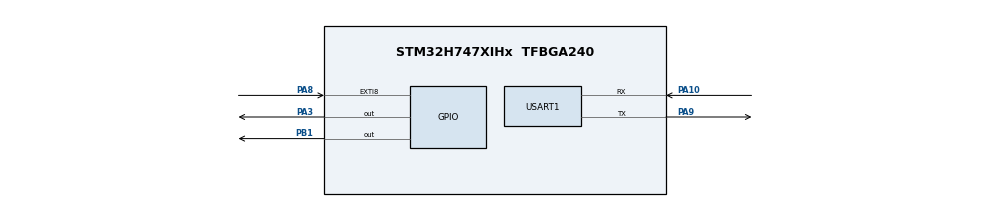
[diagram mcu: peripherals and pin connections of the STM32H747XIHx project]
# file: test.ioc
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CORTEX_M7.default_mode_Activation=1
CortexM4.IPs=CORTEX_M4\:I,FATFS_M4\:I,FREERTOS_M4\:I,IWDG2\:I,OPENAMP_M4\:I,PDM2PCM_M4\:I,PWR,RCC,RESMGR_UTILITY,SYS_M4\:I,USB_DEVICE_M4\:I,USB_HOST_M4\:I,VREFBUF,WWDG2\:I,GPIO,DMA,BDMA,MDMA,NVIC2\:I
CortexM7.IPs=CORTEX_M7\:I,FATFS_M7\:I,FREERTOS_M7\:I,IWDG1\:I,OPENAMP_M7\:I,PDM2PCM_M7\:I,PWR\:I,RCC\:I,RESMGR_UTILITY\:I,SYS\:I,USB_DEVICE_M7\:I,USB_HOST_M7\:I,VREFBUF\:I,WWDG1\:I,GPIO\:I,DMA\:I,BDMA\:I,MDMA\:I,NVIC1\:I,USART1\:I
CortexM7.Pins=PA8,PB1,PA3
Dma.Request0=USART1_TX
Dma.Request1=USART1_RX
Dma.USART1_RX.1.Direction=DMA_PERIPH_TO_MEMORY
Dma.USART1_RX.1.EventEnable=DISABLE
Dma.USART1_RX.1.FIFOMode=DMA_FIFOMODE_DISABLE
Dma.USART1_RX.1.Instance=DMA1_Stream1
Dma.USART1_RX.1.MemDataAlignment=DMA_MDATAALIGN_BYTE
Dma.USART1_RX.1.MemInc=DMA_MINC_ENABLE
Dma.USART1_RX.1.Mode=DMA_NORMAL
Dma.USART1_RX.1.PeriphDataAlignment=DMA_PDATAALIGN_BYTE
Dma.USART1_RX.1.PeriphInc=DMA_PINC_DISABLE
Dma.USART1_RX.1.Polarity=HAL_DMAMUX_REQ_GEN_RISING
Dma.USART1_RX.1.Priority=DMA_PRIORITY_LOW
Dma.USART1_RX.1.RequestNumber=1
Dma.USART1_RX.1.SignalID=NONE
Dma.USART1_RX.1.SyncEnable=DISABLE
Dma.USART1_RX.1.SyncPolarity=HAL_DMAMUX_SYNC_NO_EVENT
Dma.USART1_RX.1.SyncRequestNumber=1
Dma.USART1_RX.1.SyncSignalID=NONE
Dma.USART1_TX.0.Direction=DMA_MEMORY_TO_PERIPH
Dma.USART1_TX.0.EventEnable=DISABLE
Dma.USART1_TX.0.FIFOMode=DMA_FIFOMODE_DISABLE
Dma.USART1_TX.0.Instance=DMA1_Stream0
Dma.USART1_TX.0.MemDataAlignment=DMA_MDATAALIGN_BYTE
Dma.USART1_TX.0.MemInc=DMA_MINC_ENABLE
Dma.USART1_TX.0.Mode=DMA_NORMAL
Dma.USART1_TX.0.PeriphDataAlignment=DMA_PDATAALIGN_BYTE
Dma.USART1_TX.0.PeriphInc=DMA_PINC_DISABLE
Dma.USART1_TX.0.Polarity=HAL_DMAMUX_REQ_GEN_RISING
Dma.USART1_TX.0.Priority=DMA_PRIORITY_LOW
Dma.USART1_TX.0.RequestNumber=1
Dma.USART1_TX.0.SignalID=NONE
Dma.USART1_TX.0.SyncEnable=DISABLE
Dma.USART1_TX.0.SyncPolarity=HAL_DMAMUX_SYNC_NO_EVENT
Dma.USART1_TX.0.SyncRequestNumber=1
Dma.USART1_TX.0.SyncSignalID=NONE
IWDG1.Prescaler=IWDG_PRESCALER_64
IWDG1.Window=1500
Mcu.Family=STM32H7
Mcu.Name=STM32H747XIHx
Mcu.Package=TFBGA240
NVIC1.DMA1_Stream0_IRQn=true\:0\:0\:false\:false\:true\:false\:true\:true
NVIC1.DMA1_Stream1_IRQn=true\:0\:0\:false\:false\:true\:false\:true\:true
NVIC1.EXTI9_5_IRQn=true\:0\:0\:false\:false\:true\:true\:true\:true
NVIC1.PriorityGroup=NVIC_PRIORITYGROUP_4
NVIC1.USART1_IRQn=true\:0\:0\:false\:false\:true\:true\:true\:true
NVIC2.PriorityGroup=NVIC_PRIORITYGROUP_4
PA10.Mode=Asynchronous
PA10.PinAttribute=CortexM7
PA10.Signal=USART1_RX
PA3.PinAttribute=CortexM7
PA3.PinState=GPIO_PIN_SET
PA3.Signal=GPIO_Output
PA8.GPIO_ModeDefaultEXTI=GPIO_MODE_IT_RISING
PA8.GPIO_PuPd=GPIO_PULLDOWN
PA8.PinAttribute=CortexM7
PA8.Signal=GPXTI8
PA9.Mode=Asynchronous
PA9.PinAttribute=CortexM7
PA9.Signal=USART1_TX
PB1.PinAttribute=CortexM7
PB1.PinState=GPIO_PIN_SET
PB1.Signal=GPIO_Output
ProjectManager.HeapSize=M4-0x200,M7-0x200
ProjectManager.StackSize=M4-0x400,M7-0x400
ProjectManager.TargetToolchain=Makefile
RCC.ADCFreq_Value=129000000
RCC.APB1Freq_Value=60000000
RCC.APB2Freq_Value=30000000
RCC.APB3Freq_Value=60000000
RCC.APB4Freq_Value=60000000
RCC.CortexFreq_Value=120000000
RCC.D1PPRE=RCC_APB3_DIV2
RCC.D2PPRE1=RCC_APB1_DIV2
RCC.D2PPRE2=RCC_APB2_DIV4
RCC.D3PPRE=RCC_APB4_DIV2
RCC.DIVM1=4
RCC.DIVN1=15
RCC.HCLKFreq_Value=120000000
RCC.PLL2FRACN=0
RCC.PLL3FRACN=0
RCC.PLLFRACN=0
RCC.SYSCLKFreq_VALUE=120000000
RCC.SYSCLKSource=RCC_SYSCLKSOURCE_PLLCLK
RCC.USBFreq_Value=120000000
SYS.userName=SYS_M7
USART1.VirtualMode-Asynchronous=VM_ASYNC
VP_IWDG1_VS_IWDG.Mode=IWDG_Activate
VP_SYS_M4_VS_Systick.Mode=SysTick
VP_WWDG1_VS_WWDG.Mode=WWDG_Activate
WWDG1.Prescaler=WWDG_PRESCALER_32
board=custom

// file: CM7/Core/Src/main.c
/* USER CODE BEGIN Header */
/**
 ******************************************************************************
 * @file           : main.c
 * @brief          : Main program body
 ******************************************************************************
 * @attention
 *
 * Copyright (c) 2026 STMicroelectronics.
 * All rights reserved.
 *
 * This software is licensed under terms that can be found in the LICENSE file
 * in the root directory of this software component.
 * If no LICENSE file comes with this software, it is provided AS-IS.
 *
 ******************************************************************************
 */
/* USER CODE END Header */
#include "main.h"
#include "usart.h"
#include "wwdg.h"
#include "gpio.h"

/* USER CODE BEGIN PD */

#ifndef HSEM_ID_0
#define HSEM_ID_0 (0U) /* HW semaphore 0*/
#endif

/* USER CODE END PD */

/* USER CODE BEGIN PM */
#include <stdio.h>
/* USER CODE END PM */

void SystemClock_Config(void);

int main(void)
{
  /* USER CODE BEGIN Boot_Mode_Sequence_0 */
  int32_t timeout;
  /* USER CODE END Boot_Mode_Sequence_0 */

  /* USER CODE BEGIN Boot_Mode_Sequence_1 */
  /* Wait until CPU2 boots and enters in stop mode or timeout*/
  timeout = 0xFFFF;
  while ((__HAL_RCC_GET_FLAG(RCC_FLAG_D2CKRDY) != RESET) && (timeout-- > 0))
    ;
  if (timeout < 0)
  {
    Error_Handler();
  }
  /* USER CODE END Boot_Mode_Sequence_1 */
  /* MCU Configuration--------------------------------------------------------*/

  /* Reset of all peripherals, Initializes the Flash interface and the Systick. */
  HAL_Init();

  /* Configure the system clock */
  SystemClock_Config();
  /* USER CODE BEGIN Boot_Mode_Sequence_2 */
  /* When system initialization is finished, Cortex-M7 will release Cortex-M4 by means of
  HSEM notification */
  /*HW semaphore Clock enable*/
  __HAL_RCC_HSEM_CLK_ENABLE();
  /*Take HSEM */
  HAL_HSEM_FastTake(HSEM_ID_0);
  /*Release HSEM in order to notify the CPU2(CM4)*/
  HAL_HSEM_Release(HSEM_ID_0, 0);
  /* wait until CPU2 wakes up from stop mode */
  timeout = 0xFFFF;
  while ((__HAL_RCC_GET_FLAG(RCC_FLAG_D2CKRDY) == RESET) && (timeout-- > 0))
    ;
  if (timeout < 0)
  {
    Error_Handler();
  }
  /* USER CODE END Boot_Mode_Sequence_2 */

  /* Initialize all configured peripherals */
  MX_GPIO_Init();
  MX_USART1_UART_Init();
  MX_WWDG1_Init();
  /* USER CODE BEGIN 2 */
  printf("WWDG start\r\n");
  /* USER CODE END 2 */

  /* Infinite loop */
  while (1)
  {

    /* USER CODE BEGIN 3 */
    /* �Ϸ�ι������Լ 100~275 ms���ȵ� >100 ms����Ȧѭ�� <275 ms */
    HAL_Delay(150);
    HAL_WWDG_Refresh(&hwwdg1);
    printf("running\r\n");
    HAL_Delay(50);
  }
  /* USER CODE END 3 */
}

void SystemClock_Config(void)
{
  RCC_OscInitTypeDef RCC_OscInitStruct = {0};
  RCC_ClkInitTypeDef RCC_ClkInitStruct = {0};

  /** Supply configuration update enable
   */
  HAL_PWREx_ConfigSupply(PWR_LDO_SUPPLY);

  /** Configure the main internal regulator output voltage
   */
  __HAL_PWR_VOLTAGESCALING_CONFIG(PWR_REGULATOR_VOLTAGE_SCALE1);

  while (!__HAL_PWR_GET_FLAG(PWR_FLAG_VOSRDY))
  {
  }

  __HAL_RCC_SYSCFG_CLK_ENABLE();
  __HAL_PWR_VOLTAGESCALING_CONFIG(PWR_REGULATOR_VOLTAGE_SCALE0);

  while (!__HAL_PWR_GET_FLAG(PWR_FLAG_VOSRDY))
  {
  }

  /** Initializes the RCC Oscillators according to the specified parameters
   * in the RCC_OscInitTypeDef structure.
   */
  RCC_OscInitStruct.OscillatorType = RCC_OSCILLATORTYPE_HSI | RCC_OSCILLATORTYPE_LSI;
  RCC_OscInitStruct.HSIState = RCC_HSI_DIV1;
  RCC_OscInitStruct.HSICalibrationValue = RCC_HSICALIBRATION_DEFAULT;
  RCC_OscInitStruct.LSIState = RCC_LSI_ON;
  RCC_OscInitStruct.PLL.PLLState = RCC_PLL_ON;
  RCC_OscInitStruct.PLL.PLLSource = RCC_PLLSOURCE_HSI;
  RCC_OscInitStruct.PLL.PLLM = 4;
  RCC_OscInitStruct.PLL.PLLN = 60;
  RCC_OscInitStruct.PLL.PLLP = 2;
  RCC_OscInitStruct.PLL.PLLQ = 2;
  RCC_OscInitStruct.PLL.PLLR = 2;
  RCC_OscInitStruct.PLL.PLLRGE = RCC_PLL1VCIRANGE_3;
  RCC_OscInitStruct.PLL.PLLVCOSEL = RCC_PLL1VCOWIDE;
  RCC_OscInitStruct.PLL.PLLFRACN = 0;
  if (HAL_RCC_OscConfig(&RCC_OscInitStruct) != HAL_OK)
  {
    Error_Handler();
  }

  /** Initializes the CPU, AHB and APB buses clocks
   */
  RCC_ClkInitStruct.ClockType = RCC_CLOCKTYPE_HCLK | RCC_CLOCKTYPE_SYSCLK | RCC_CLOCKTYPE_PCLK1 | RCC_CLOCKTYPE_PCLK2 | RCC_CLOCKTYPE_D3PCLK1 | RCC_CLOCKTYPE_D1PCLK1;
  RCC_ClkInitStruct.SYSCLKSource = RCC_SYSCLKSOURCE_PLLCLK;
  RCC_ClkInitStruct.SYSCLKDivider = RCC_SYSCLK_DIV1;
  RCC_ClkInitStruct.AHBCLKDivider = RCC_HCLK_DIV2;
  RCC_ClkInitStruct.APB3CLKDivider = RCC_APB3_DIV2;
  RCC_ClkInitStruct.APB1CLKDivider = RCC_APB1_DIV2;
  RCC_ClkInitStruct.APB2CLKDivider = RCC_APB2_DIV2;
  RCC_ClkInitStruct.APB4CLKDivider = RCC_APB4_DIV2;

  if (HAL_RCC_ClockConfig(&RCC_ClkInitStruct, FLASH_LATENCY_4) != HAL_OK)
  {
    Error_Handler();
  }
}

void Error_Handler(void)
{
  __disable_irq();
  while (1)
  {
  }
}
